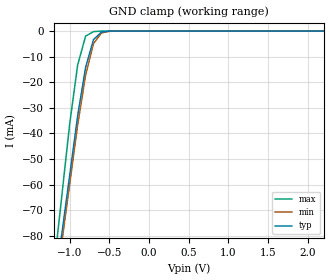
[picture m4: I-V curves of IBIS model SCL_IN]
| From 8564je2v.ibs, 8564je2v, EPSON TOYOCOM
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|   Model INPUT
[Model]   SCL_IN
Model_type   Input
Polarity   Non-Inverting
Vinl =   0.6V
Vinh =   1.4V
C_comp   5pF   5pF   5pF
[Temperature Range]   25.00   85.00   -40.00
[Voltage Range]   2.0V   1.8V   2.2V
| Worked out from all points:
|   GND clamp passes 1 mA (typ) near -0.62 V on its own axis
[GND_clamp]
| voltage   I(typ)   I(min)   I(max)
-2.2V     -333.9mA   -335.6mA   -376.4mA
-1.2V     -102.5mA   -105.8mA   -92.9mA
-1.1V     -79.4mA    -82.8mA    -64.6mA
-1V       -56.3mA    -59.8mA    -36.2mA
-900mV    -33.1mA    -36.8mA    -13.3mA
-800mV    -14.2mA    -17.3mA    -2mA
-700mV    -3.3mA     -4.9mA     -200uA
-600mV    -400uA     -700uA     0A
-500mV    0A         -100uA     0A
2.2V      0A         0A         0A
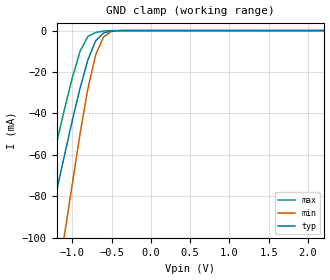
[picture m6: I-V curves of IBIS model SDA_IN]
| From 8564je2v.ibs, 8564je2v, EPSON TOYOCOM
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[Model]   SDA_IN
Model_type   Input
Polarity   Non-Inverting
Vinl =   0.6V
Vinh =   1.4V
C_comp   5pF   5pF   5pF
[Temperature Range]   25.00   85.00   -40.00
[Voltage Range]   2.0V   1.8V   2.2V
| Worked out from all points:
|   GND clamp passes 1 mA (typ) near -0.59 V on its own axis
[GND_clamp]
| voltage   I(typ)   I(min)   I(max)
-2.2V     -246.7mA   -369.2mA   -215.6mA
-1.5V     -128.1mA   -197.1mA   -102.7mA
-1.4V     -111.2mA   -172.6mA   -86.5mA
-1.3V     -94.3mA    -148mA     -70.4mA
-1.1V     -60.4mA    -98.8mA    -38.1mA
-1V       -43.5mA    -74.2mA    -22.9mA
-900mV    -27.7mA    -49.7mA    -9.9mA
-800mV    -14mA      -27.8mA    -2.8mA
-700mV    -4.8mA     -11.5mA    -900uA
-600mV    -1.1mA     -3mA       -200uA
-500mV    -300uA     -400uA     0A
2.2V      0A         0A         0A
